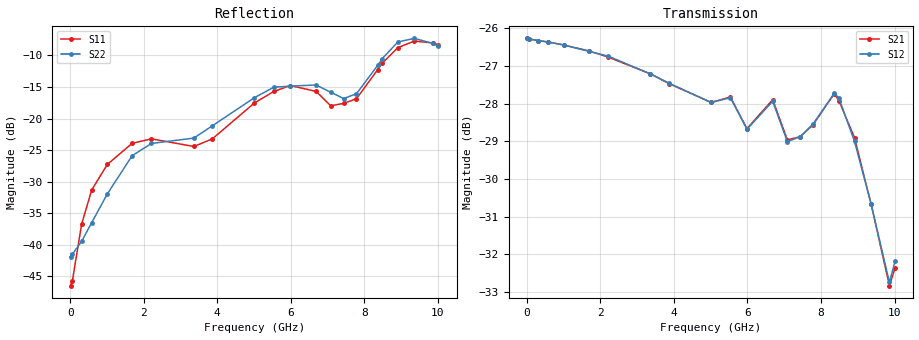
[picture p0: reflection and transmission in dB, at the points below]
! Device ID: PE43705
! Serial: 1
! Insertion: A
! Impedance: 50 ohm
! Temp: 25C
! VDD: 3.400V
! Attenuation Step: 25.25dB
#  Hz  S  RI  R  50
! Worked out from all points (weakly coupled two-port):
!   401 points, 10 MHz to 10.01 GHz, reference 50 ohm
!   highest |S21| = -26.26 dB at 10 MHz (marker M1); lowest = -32.8 dB at 9.86 GHz (marker M2)
!   lowest |S11| = -46.5 dB at 10 MHz (marker M3), VSWR 1.01, Z = 49.5 + j0.0446 ohm
!   |S11| at or under -10 dB: start of sweep to 8.671 GHz
!   |S22| runs from -41.9 to -7.3 dB; largest |S21 - S12| = 0.00069
!   S11 on the Smith chart (normalised r, x): 10 MHz: 0.99, +0.00; 7.435 GHz: 0.82, +0.16; 8.485 GHz: 0.84, +0.50; 9.36 GHz: 0.55, +0.50; 10.01 GHz: 0.49, +0.27
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1e7  -0.00472 0.000451  0.0486 -0.000182  0.0486 -0.000159  0.00806 0.000308
6e7  -0.00449 0.00261  0.0485 -0.000842  0.0485 -0.000823  0.00826 0.00169
3.1e8  -0.00674 0.0129  0.0481 -0.00399  0.0481 -0.00398  0.00587 0.00887
5.85e8  -0.0147 0.0229  0.0475 -0.00733  0.0475 -0.00728  -0.0016 0.0149
1.01e9  -0.0335 0.0275  0.046 -0.0123  0.046 -0.0123  -0.0206 0.0147
1.685e9  -0.0612 0.0176  0.0426 -0.0193  0.0425 -0.0194  -0.0508 0.00216
2.21e9  -0.069 0.00298  0.039 -0.0242  0.0391 -0.0243  -0.0627 -0.0101
3.36e9  -0.0599 0.00492  0.0294 -0.0322  0.0294 -0.0322  -0.07 -0.00151
3.86e9  -0.063 0.0278  0.0251 -0.0341  0.0252 -0.0341  -0.0856 0.0175
5.01e9  -0.0993 0.0884  0.0165 -0.0364  0.0167 -0.0363  -0.1279 0.0711
5.535e9  -0.1287 0.1014  0.0124 -0.0387  0.0124 -0.0386  -0.15 0.094
5.985e9  -0.1506 0.1033  0.00849 -0.0359  0.00861 -0.0358  -0.1494 0.1018
6.685e9  -0.1419 0.0827  0.00493 -0.04  0.00492 -0.0398  -0.1511 0.1059
7.085e9  -0.1082 0.065  -0.00178 -0.0356  -0.00188 -0.0354  -0.1139 0.1147
7.435e9  -0.0895 0.0969  -0.000508 -0.036  -0.00066 -0.036  -0.0736 0.1239
7.785e9  -0.0434 0.1368  -0.00152 -0.0373  -0.00142 -0.0374  -0.0418 0.1515
8.36e9  -0.00868 0.2435  -0.0115 -0.0394  -0.0114 -0.0395  -0.0185 0.2628
8.485e9  -0.0148 0.2734  -0.0142 -0.0376  -0.014 -0.038  -0.0229 0.2973
8.91e9  -0.0711 0.3581  -0.0184 -0.0308  -0.0183 -0.0304  -0.0761 0.3972
9.36e9  -0.1705 0.3737  -0.017 -0.0239  -0.017 -0.0239  -0.1587 0.4017
9.86e9  -0.2779 0.284  -0.00849 -0.0212  -0.00862 -0.0214  -0.2686 0.2882
1.001e10  -0.3019 0.2367  -0.00567 -0.0234  -0.00535 -0.024  -0.2963 0.2282
